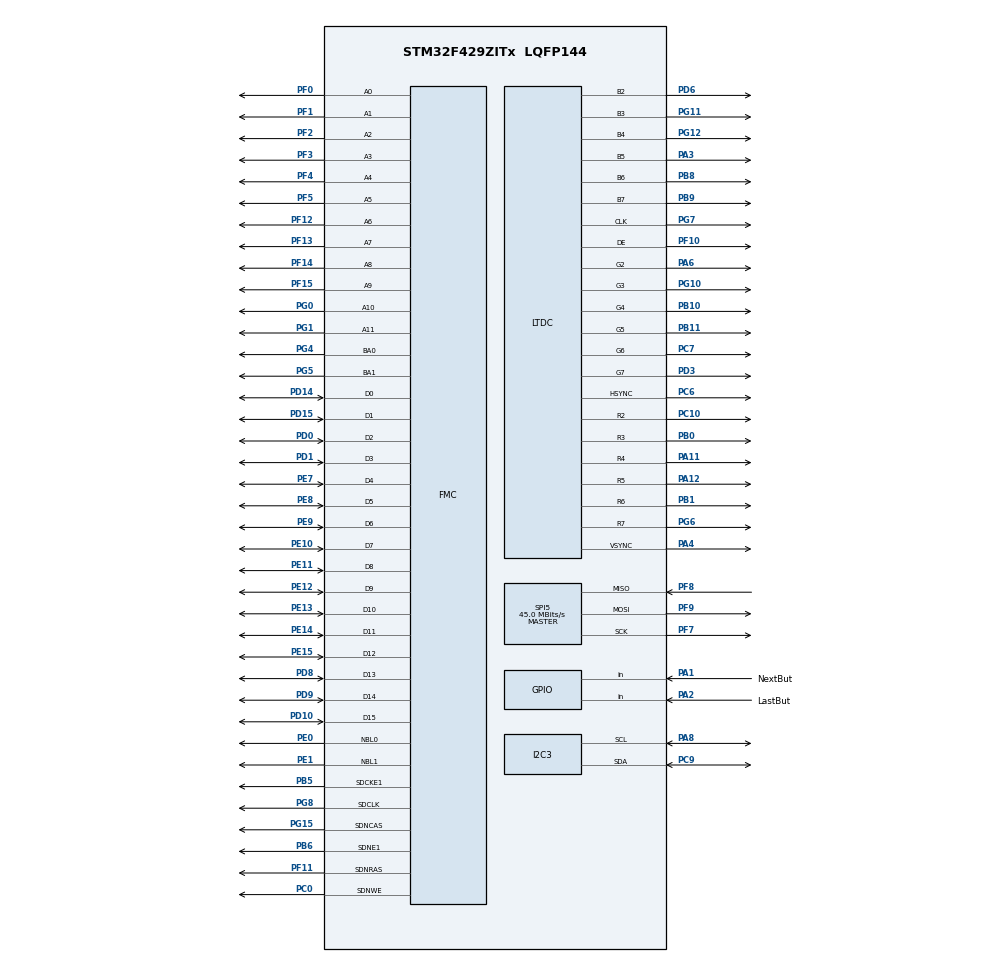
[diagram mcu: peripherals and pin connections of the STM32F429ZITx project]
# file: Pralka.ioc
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DMA2D.ColorMode=DMA2D_OUTPUT_RGB565
LTDC.ActiveH=320
LTDC.ActiveW=240
Mcu.Family=STM32F4
Mcu.Name=STM32F429ZITx
Mcu.Package=LQFP144
NVIC.PriorityGroup=NVIC_PRIORITYGROUP_4
PA1.GPIO_Label=NextBut
PA1.Signal=GPIO_Input
PA11.Mode=RGB666
PA11.Signal=LTDC_R4
PA12.Mode=RGB666
PA12.Signal=LTDC_R5
PA2.GPIO_Label=LastBut
PA2.Signal=GPIO_Input
PA3.Mode=RGB666
PA3.Signal=LTDC_B5
PA4.Mode=RGB666
PA4.Signal=LTDC_VSYNC
PA6.Mode=RGB666
PA6.Signal=LTDC_G2
PA8.Mode=I2C
PA8.Signal=I2C3_SCL
PB0.Mode=RGB666
PB0.Signal=LTDC_R3
PB1.Mode=RGB666
PB1.Signal=LTDC_R6
PB10.Mode=RGB666
PB10.Signal=LTDC_G4
PB11.Mode=RGB666
PB11.Signal=LTDC_G5
PB5.Mode=SdramChipSelect2_1
PB5.Signal=FMC_SDCKE1
PB6.Mode=SdramChipSelect2_1
PB6.Signal=FMC_SDNE1
PB8.Mode=RGB666
PB8.Signal=LTDC_B6
PB9.Mode=RGB666
PB9.Signal=LTDC_B7
PC0.Signal=FMC_SDNWE
PC10.Mode=RGB666
PC10.Signal=LTDC_R2
PC6.Mode=RGB666
PC6.Signal=LTDC_HSYNC
PC7.Mode=RGB666
PC7.Signal=LTDC_G6
PC9.Mode=I2C
PC9.Signal=I2C3_SDA
PD0.Signal=FMC_D2_DA2
PD1.Signal=FMC_D3_DA3
PD10.Signal=FMC_D15_DA15
PD14.Signal=FMC_D0_DA0
PD15.Signal=FMC_D1_DA1
PD3.Mode=RGB666
PD3.Signal=LTDC_G7
PD6.Mode=RGB666
PD6.Signal=LTDC_B2
PD8.Signal=FMC_D13_DA13
PD9.Signal=FMC_D14_DA14
PE0.Signal=FMC_NBL0
PE1.Signal=FMC_NBL1
PE10.Signal=FMC_D7_DA7
PE11.Signal=FMC_D8_DA8
PE12.Signal=FMC_D9_DA9
PE13.Signal=FMC_D10_DA10
PE14.Signal=FMC_D11_DA11
PE15.Signal=FMC_D12_DA12
PE7.Signal=FMC_D4_DA4
PE8.Signal=FMC_D5_DA5
PE9.Signal=FMC_D6_DA6
PF0.Signal=FMC_A0
PF1.Signal=FMC_A1
PF10.Mode=RGB666
PF10.Signal=LTDC_DE
PF11.Signal=FMC_SDNRAS
PF12.Signal=FMC_A6
PF13.Signal=FMC_A7
PF14.Signal=FMC_A8
PF15.Signal=FMC_A9
PF2.Signal=FMC_A2
PF3.Signal=FMC_A3
PF4.Signal=FMC_A4
PF5.Signal=FMC_A5
PF7.Mode=Full_Duplex_Master
PF7.Signal=SPI5_SCK
PF8.Mode=Full_Duplex_Master
PF8.Signal=SPI5_MISO
PF9.Mode=Full_Duplex_Master
PF9.Signal=SPI5_MOSI
PG0.Signal=FMC_A10
PG1.Signal=FMC_A11
PG10.Mode=RGB666
PG10.Signal=LTDC_G3
PG11.Mode=RGB666
PG11.Signal=LTDC_B3
PG12.Mode=RGB666
PG12.Signal=LTDC_B4
PG15.Signal=FMC_SDNCAS
PG4.Signal=FMC_A14_BA0
PG5.Signal=FMC_A15_BA1
PG6.Mode=RGB666
PG6.Signal=LTDC_R7
PG7.Mode=RGB666
PG7.Signal=LTDC_CLK
PG8.Signal=FMC_SDCLK
PH0/OSC_IN.Mode=HSE-External-Oscillator
PH0/OSC_IN.Signal=RCC_OSC_IN
PH1/OSC_OUT.Mode=HSE-External-Oscillator
PH1/OSC_OUT.Signal=RCC_OSC_OUT
ProjectManager.HeapSize=0x200
ProjectManager.StackSize=0x400
ProjectManager.TargetToolchain=STM32CubeIDE
RCC.48MHZClocksFreq_Value=90000000
RCC.AHBFreq_Value=180000000
RCC.APB1CLKDivider=RCC_HCLK_DIV4
RCC.APB1Freq_Value=45000000
RCC.APB1TimFreq_Value=90000000
RCC.APB2CLKDivider=RCC_HCLK_DIV2
RCC.APB2Freq_Value=90000000
RCC.APB2TimFreq_Value=180000000
RCC.CortexFreq_Value=180000000
RCC.HCLKFreq_Value=180000000
RCC.HSE_VALUE=8000000
RCC.HSI_VALUE=16000000
RCC.LSE_VALUE=32768
RCC.PLLN=180
RCC.PLLSAIR=2
RCC.PLLSourceVirtual=RCC_PLLSOURCE_HSE
RCC.SYSCLKFreq_VALUE=180000000
RCC.SYSCLKSource=RCC_SYSCLKSOURCE_PLLCLK
RCC.VCOOutputFreq_Value=360000000
SH.FMC_A0.0=FMC_A0,12b-sda1
SH.FMC_A1.0=FMC_A1,12b-sda1
SH.FMC_A10.0=FMC_A10,12b-sda1
SH.FMC_A11.0=FMC_A11,12b-sda1
SH.FMC_A14_BA0.0=FMC_BA0,FourSdramBanks1
SH.FMC_A15_BA1.0=FMC_BA1,FourSdramBanks1
SH.FMC_A2.0=FMC_A2,12b-sda1
SH.FMC_A3.0=FMC_A3,12b-sda1
SH.FMC_A4.0=FMC_A4,12b-sda1
SH.FMC_A5.0=FMC_A5,12b-sda1
SH.FMC_A6.0=FMC_A6,12b-sda1
SH.FMC_A7.0=FMC_A7,12b-sda1
SH.FMC_A8.0=FMC_A8,12b-sda1
SH.FMC_A9.0=FMC_A9,12b-sda1
SH.FMC_D0_DA0.0=FMC_D0,sd-16b-d1
SH.FMC_D10_DA10.0=FMC_D10,sd-16b-d1
SH.FMC_D11_DA11.0=FMC_D11,sd-16b-d1
SH.FMC_D12_DA12.0=FMC_D12,sd-16b-d1
SH.FMC_D13_DA13.0=FMC_D13,sd-16b-d1
SH.FMC_D14_DA14.0=FMC_D14,sd-16b-d1
SH.FMC_D15_DA15.0=FMC_D15,sd-16b-d1
SH.FMC_D1_DA1.0=FMC_D1,sd-16b-d1
SH.FMC_D2_DA2.0=FMC_D2,sd-16b-d1
SH.FMC_D3_DA3.0=FMC_D3,sd-16b-d1
SH.FMC_D4_DA4.0=FMC_D4,sd-16b-d1
SH.FMC_D5_DA5.0=FMC_D5,sd-16b-d1
SH.FMC_D6_DA6.0=FMC_D6,sd-16b-d1
SH.FMC_D7_DA7.0=FMC_D7,sd-16b-d1
SH.FMC_D8_DA8.0=FMC_D8,sd-16b-d1
SH.FMC_D9_DA9.0=FMC_D9,sd-16b-d1
SH.FMC_NBL0.0=FMC_NBL0,Sd2ByteEnable1
SH.FMC_NBL1.0=FMC_NBL1,Sd2ByteEnable1
SH.FMC_SDCLK.0=FMC_SDCLK,12b-sda1
SH.FMC_SDNCAS.0=FMC_SDNCAS,12b-sda1
SH.FMC_SDNRAS.0=FMC_SDNRAS,12b-sda1
SH.FMC_SDNWE.0=FMC_SDNWE,12b-sda1
SPI5.BaudRatePrescaler=SPI_BAUDRATEPRESCALER_2
SPI5.CalculateBaudRate=45.0 MBits/s
SPI5.Direction=SPI_DIRECTION_2LINES
SPI5.Mode=SPI_MODE_MASTER
SPI5.VirtualType=VM_MASTER
VP_DMA2D_VS_DMA2D.Mode=DMA2D_Activate
board=custom

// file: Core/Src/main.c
/* USER CODE BEGIN Header */
/**
  ******************************************************************************
  * @file           : main.c
  * @brief          : Main program body
  ******************************************************************************
  * @attention
  *
  * Copyright (c) 2024 STMicroelectronics.
  * All rights reserved.
  *
  * This software is licensed under terms that can be found in the LICENSE file
  * in the root directory of this software component.
  * If no LICENSE file comes with this software, it is provided AS-IS.
  *
  ******************************************************************************
  */
/* USER CODE END Header */
#include "main.h"
#include "stm32f429i_discovery_lcd.h"

typedef struct {
    char name[20];      // Nazwa programu
    uint16_t time;      // Czas trwania
    uint16_t temperature; // Temperatura
} WashingProgram;

WashingProgram programs[] = {
    {"Czyszczenie", 30, 60},
    {"Plukanie", 10, 30},
    {"Szybkie pranie", 15, 40},
    {"Delikatne", 40, 30},
    {"Bawelna", 60, 60}
};
#define NUM_PROGRAMS (sizeof(programs) / sizeof(programs[0]))

int current_program = 0;  // Indeks aktualnego programu

void SystemClock_Config(void);
static void MX_GPIO_Init(void);
static void MX_DMA2D_Init(void);
static void MX_FMC_Init(void);
static void MX_I2C3_Init(void);
static void MX_LTDC_Init(void);
static void MX_SPI5_Init(void);
void displayProgram(void); // Function to display the current program

int main(void)
{

  /* MCU Configuration--------------------------------------------------------*/
  HAL_Init();
  SystemClock_Config();
  MX_GPIO_Init();
  MX_DMA2D_Init();
  MX_FMC_Init();
  MX_I2C3_Init();
  MX_LTDC_Init();
  MX_SPI5_Init();

  /* USER CODE BEGIN 2 */
  BSP_LCD_Init();
  BSP_LCD_LayerDefaultInit(LCD_BACKGROUND_LAYER, LCD_FRAME_BUFFER);
  BSP_LCD_Clear(LCD_COLOR_RED);
  display_program(programs[current_program]);
  /* USER CODE END 2 */

  /* Infinite loop */
  while (1)
  {
      if (HAL_GPIO_ReadPin(GPIOA, NextBut_Pin) == GPIO_PIN_SET) {
          // Przejdź do następnego programu
          current_program = (current_program + 1) % NUM_PROGRAMS;
          display_program(programs[current_program]);
          HAL_Delay(200);
      }

      if (HAL_GPIO_ReadPin(GPIOA, LastBut_Pin) == GPIO_PIN_SET) {
          // Przejdź do poprzedniego programu
          current_program = (current_program - 1 + NUM_PROGRAMS) % NUM_PROGRAMS;
          display_program(programs[current_program]);
          HAL_Delay(200);
      }

      HAL_Delay(100);
  }
}

/* Function to display the current selected program */
void display_program(WashingProgram program) {
      char buffer[40];
      sprintf(buffer, "Prog: %s", program.name);
      BSP_LCD_DisplayStringAtLine(0, (uint8_t*)buffer);

      sprintf(buffer, "Czas: %d min", program.time);
      BSP_LCD_DisplayStringAtLine(1, (uint8_t*)buffer);

      sprintf(buffer, "Temp: %d C", program.temperature);
      BSP_LCD_DisplayStringAtLine(2, (uint8_t*)buffer);
}

void SystemClock_Config(void)
{
  RCC_OscInitTypeDef RCC_OscInitStruct = {0};
  RCC_ClkInitTypeDef RCC_ClkInitStruct = {0};

  /** Configure the main internal regulator output voltage
  */
  __HAL_RCC_PWR_CLK_ENABLE();
  __HAL_PWR_VOLTAGESCALING_CONFIG(PWR_REGULATOR_VOLTAGE_SCALE1);

  /** Initializes the RCC Oscillators according to the specified parameters
  * in the RCC_OscInitTypeDef structure.
  */
  RCC_OscInitStruct.OscillatorType = RCC_OSCILLATORTYPE_HSE;
  RCC_OscInitStruct.HSEState = RCC_HSE_ON;
  RCC_OscInitStruct.PLL.PLLState = RCC_PLL_ON;
  RCC_OscInitStruct.PLL.PLLSource = RCC_PLLSOURCE_HSE;
  RCC_OscInitStruct.PLL.PLLM = 16;
  RCC_OscInitStruct.PLL.PLLN = 180;
  RCC_OscInitStruct.PLL.PLLP = RCC_PLLP_DIV2;
  RCC_OscInitStruct.PLL.PLLQ = 4;
  if (HAL_RCC_OscConfig(&RCC_OscInitStruct) != HAL_OK)
  {
    Error_Handler();
  }

  /** Activate the Over-Drive mode
  */
  if (HAL_PWREx_EnableOverDrive() != HAL_OK)
  {
    Error_Handler();
  }

  /** Initializes the CPU, AHB and APB buses clocks
  */
  RCC_ClkInitStruct.ClockType = RCC_CLOCKTYPE_HCLK|RCC_CLOCKTYPE_SYSCLK
                              |RCC_CLOCKTYPE_PCLK1|RCC_CLOCKTYPE_PCLK2;
  RCC_ClkInitStruct.SYSCLKSource = RCC_SYSCLKSOURCE_PLLCLK;
  RCC_ClkInitStruct.AHBCLKDivider = RCC_SYSCLK_DIV1;
  RCC_ClkInitStruct.APB1CLKDivider = RCC_HCLK_DIV4;
  RCC_ClkInitStruct.APB2CLKDivider = RCC_HCLK_DIV2;

  if (HAL_RCC_ClockConfig(&RCC_ClkInitStruct, FLASH_LATENCY_5) != HAL_OK)
  {
    Error_Handler();
  }
}

/* Other necessary initialization functions */

static void MX_DMA2D_Init(void) { /* Code for DMA2D initialization */ }
static void MX_I2C3_Init(void) { /* Code for I2C3 initialization */ }
static void MX_LTDC_Init(void) { /* Code for LTDC initialization */ }
static void MX_SPI5_Init(void) { /* Code for SPI5 initialization */ }
static void MX_FMC_Init(void) { /* Code for FMC initialization */ }
static void MX_GPIO_Init(void)
{
  GPIO_InitTypeDef GPIO_InitStruct = {0};

  /* GPIO Ports Clock Enable */
  __HAL_RCC_GPIOA_CLK_ENABLE();

  /*Configure GPIO pins : NextBut_Pin LastBut_Pin */
  GPIO_InitStruct.Pin = NextBut_Pin | LastBut_Pin;
  GPIO_InitStruct.Mode = GPIO_MODE_INPUT;
  GPIO_InitStruct.Pull = GPIO_NOPULL;
  HAL_GPIO_Init(GPIOA, &GPIO_InitStruct);
}

void Error_Handler(void)
{
  __disable_irq();
  while (1)
  {
  }
}
